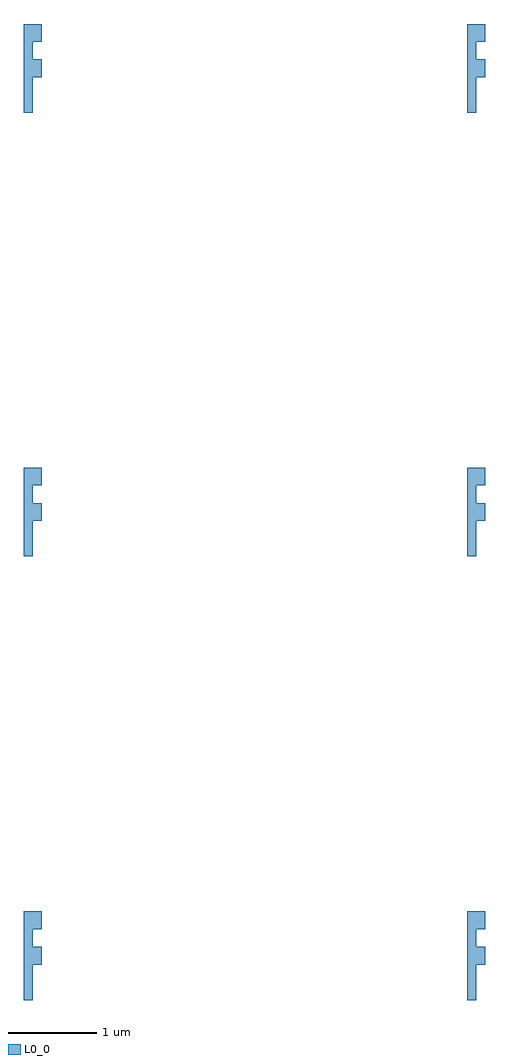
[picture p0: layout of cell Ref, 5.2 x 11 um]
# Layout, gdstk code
import gdstk
lib = gdstk.Library(unit=1e-6, precision=1e-09)
def P(c, l, *ps):  # polygons
    for p in ps: c.add(gdstk.Polygon(p, *l))
L0_0 = (0, 0)

base = lib.new_cell('Base')
P(base, L0_0, [(0,0),(0,1),(0.2,1),(0.2,0.8),(0.1,0.8),(0.1,0.6),(0.2,0.6),(0.2,0.4),(0.1,0.4),(0.1,0)])

ref = lib.new_cell('Ref')
r = gdstk.Reference(base, (0,0)); r.repetition = gdstk.Repetition(2, 3, v1=(5,0), v2=(0,5)); ref.add(r)

lib.write_gds('Ref.gds')
